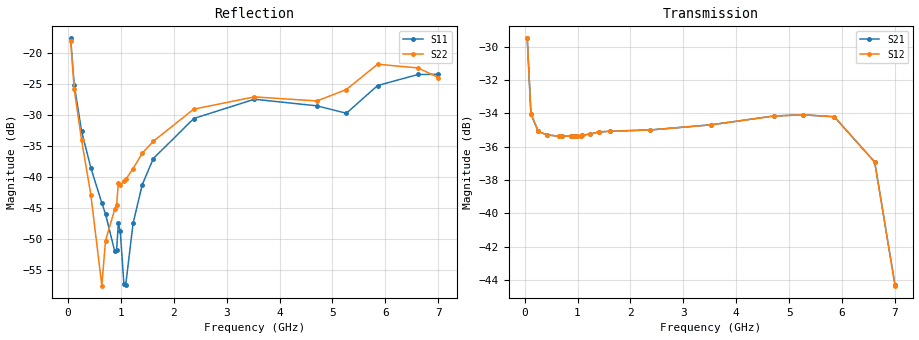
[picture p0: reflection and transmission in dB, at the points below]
! Integrated Device Technology
! Corporate Headquarters
! 6024 Silver Creek Valley Road
! San Jose, CA 95138  USA
! Phone:  1-408-284-8200
! Toll Free:  1-800-223-1366
! Webpage:  http://www.idt.com/
! Timing and RF Division
! 515 Groton Road, Suite 102
! Westford, MA 01886-6024
! Device:  F2258
! Description: Voltage Variable RF Attenuator
! Frequency:  50.0 -  6000.00 MHz
! Package:  3x3 mm Thin QFN Plastic Package: 16 pin
! Ports:  2 RF, 2 DC
!  Pin  1  = NC
!  Pin  2  = NC
!  Pin  3  = RF2  = Port 2
!  Pin  4  = GND
!  Pin  5  = Vdd
!  Pin  6  = NC
!  Pin  7  = VCTRL
!  Pin  8  = NC
!  Pin  9  = GND
!  Pin 10  = RF1  = Port 1
!  Pin 11  = NC
!  Pin 12  = NC
!  Pin 13  = NC
!  Pin 14  = NC
!  Pin 15  = NC
!  Pin 16  = NC
! Vcntrl:  2.200 Volts
! Vdd:  +3.300 Volts
! Current:  1.150 mA
! Data:  The device was measured on a the F2258 evaluation board which has
!  individual transmission lines to the RF pins.  Data was collected
!  using a calibrated network analyzer.  The evaluation board was
!  de-embedded using a TRL calibration technique.
!  The reference plane is the edge of the package pin.
! Misc:  SN 10
!  Action Tracker AT0285
! Date Measured:  2014-12-10
! Date:  2016-01-13  MJV
! Note:
!  Integrated Device Technology supplies this data as a sample of measured
!  data at the package pin for this product.  Your particular data for this
!  product may vary.
!  Data was taken at 25 degrees C.
!  Integrated Device Technology reserves the right to change this data at anytime.
!Freq_(GHz)  S11M_(dB)  S11P_(deg)  S21M_(dB)  S21P_(deg)  S12M_(dB)  S12P_(deg)  S22M_(dB)  S22P_(deg)
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# GHz S dB R 50
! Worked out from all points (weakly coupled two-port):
!   201 points, 50 MHz to 7 GHz, reference 50 ohm
!   highest |S21| = -29.50 dB at 50 MHz (marker M1); lowest = -44.3 dB at 7 GHz (marker M2)
!   lowest |S11| = -57.5 dB at 1.093 GHz (marker M3), VSWR 1.00, Z = 49.9 + j0.116 ohm
!   |S11| at or under -10 dB: start of sweep to end of sweep
!   |S22| runs from -57.6 to -17.9 dB; largest |S21 - S12| = 7.8e-05
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0.05  -17.55 -111.0  -29.50 -68.2  -29.50 -68.2  -17.94 -110.9
0.1195  -25.12 -106.9  -34.02 -36.7  -34.02 -36.7  -25.81 -105.3
0.2585  -32.61 -111.8  -35.09 -18.7  -35.09 -18.7  -34.06 -108.0
0.43225  -38.50 -119.7  -35.30 -12.5  -35.30 -12.4  -42.84 -115.3
0.64075  -44.23 -128.0  -35.37 -9.7  -35.37 -9.7  -57.61 160.9
0.71025  -46.00 -137.7  -35.37 -9.2  -35.37 -9.2  -50.30 113.3
0.884  -52.03 166.1  -35.37 -8.5  -35.37 -8.5  -45.26 101.8
0.91875  -51.90 149.8  -35.36 -8.4  -35.36 -8.4  -44.58 100.6
0.9535  -47.51 -162.9  -35.38 -8.3  -35.37 -8.3  -41.00 113.0
0.98825  -48.73 -174.5  -35.36 -8.2  -35.36 -8.2  -41.27 110.2
1.05775  -57.32 154.7  -35.34 -8.0  -35.34 -8.0  -40.71 94.3
1.0925  -57.46 119.5  -35.32 -8.0  -35.32 -7.9  -40.40 90.6
1.2315  -47.50 47.1  -35.24 -8.0  -35.25 -8.0  -38.65 70.1
1.40525  -41.23 33.9  -35.12 -8.6  -35.12 -8.6  -36.14 59.0
1.61375  -37.02 32.9  -35.07 -9.7  -35.08 -9.7  -34.23 47.7
2.37825  -30.53 48.2  -35.00 -13.3  -35.00 -13.3  -29.01 40.3
3.525  -27.41 91.7  -34.69 -19.8  -34.69 -19.7  -27.03 65.3
4.7065  -28.48 95.6  -34.16 -28.9  -34.17 -28.9  -27.69 56.7
5.2625  -29.68 54.3  -34.09 -35.1  -34.09 -35.1  -25.84 19.4
5.85325  -25.19 29.8  -34.21 -45.7  -34.20 -45.6  -21.74 -3.7
6.61775  -23.40 49.7  -36.92 -68.7  -36.94 -68.7  -22.34 -45.3
7  -23.37 84.5  -44.28 -62.0  -44.35 -61.4  -23.90 -129.6
